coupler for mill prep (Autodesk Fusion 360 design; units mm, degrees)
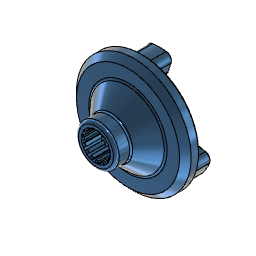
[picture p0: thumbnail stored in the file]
base_feature "Base Feature1"
base_feature "Base Feature1" bodies "Body1"
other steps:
create_component "CreateComponent1"
named bodies: "Body1"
